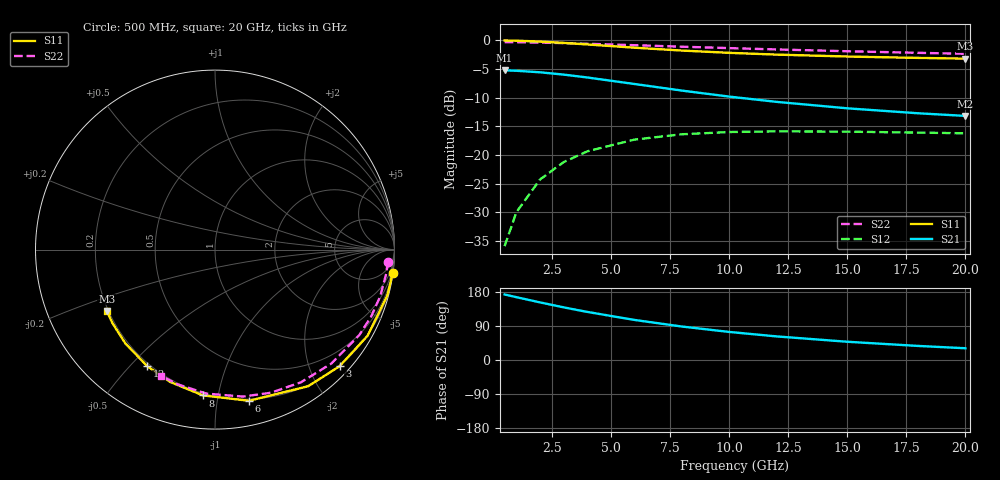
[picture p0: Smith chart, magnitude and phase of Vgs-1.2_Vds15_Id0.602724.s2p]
# Hz S RI R 50
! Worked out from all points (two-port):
!   12 points, 500 MHz to 20 GHz, reference 50 ohm
!   highest |S21| = -5.23 dB at 500 MHz (marker M1); lowest = -13.2 dB at 20 GHz (marker M2)
!   |S21| within 3 dB of the highest: start of sweep to 7.085 GHz
!   lowest |S11| = -3.2 dB at 20 GHz (marker M3), VSWR 5.51, Z = 9.68 - j12.7 ohm
!   |S11| at or under -10 dB: nowhere
!   |S22| runs from -2.3 to -0.3 dB; largest |S21 - S12| = 0.55
!   S11 on the Smith chart (normalised r, x): 500 MHz: 0, -15; 3 GHz: 0.19, -2.52; 6 GHz: 0.19, -1.23; 8 GHz: 0.19, -0.90; 12 GHz: 0.19, -0.56; 20 GHz: 0.19, -0.25
5e8  0.9898 -0.1307  -0.5432 0.068  0.00152 0.016  0.963 -0.0668
1e9  0.9599 -0.2569  -0.5264 0.1334  0.00598 0.0312  0.9543 -0.1327
2e9  0.8496 -0.4805  -0.465 0.2475  0.0222 0.057  0.9209 -0.2591
3e9  0.6938 -0.6499  -0.3792 0.3303  0.0447 0.0743  0.8694 -0.3742
4e9  0.5191 -0.7612  -0.2846 0.3799  0.0691 0.0826  0.804 -0.476
6e9  0.1892 -0.8423  -0.1128 0.4008  0.1116 0.0785  0.6483 -0.635
8e9  -0.0673 -0.8123  0.0106 0.3646  0.1391 0.0604  0.4784 -0.7396
1e10  -0.2496 -0.7375  0.0886 0.3109  0.1537 0.0394  0.3109 -0.7975
1.2e10  -0.3766 -0.6504  0.1352 0.2576  0.1596 0.0204  0.1548 -0.8189
1.5e10  -0.4992 -0.5229  0.1705 0.1904  0.1598 -0.0022  -0.0485 -0.8023
1.8e10  -0.5718 -0.4092  0.1844 0.1395  0.1558 -0.0183  -0.2119 -0.7492
2e10  -0.6029 -0.3416  0.188 0.113  0.1524 -0.0264  -0.3004 -0.7025
